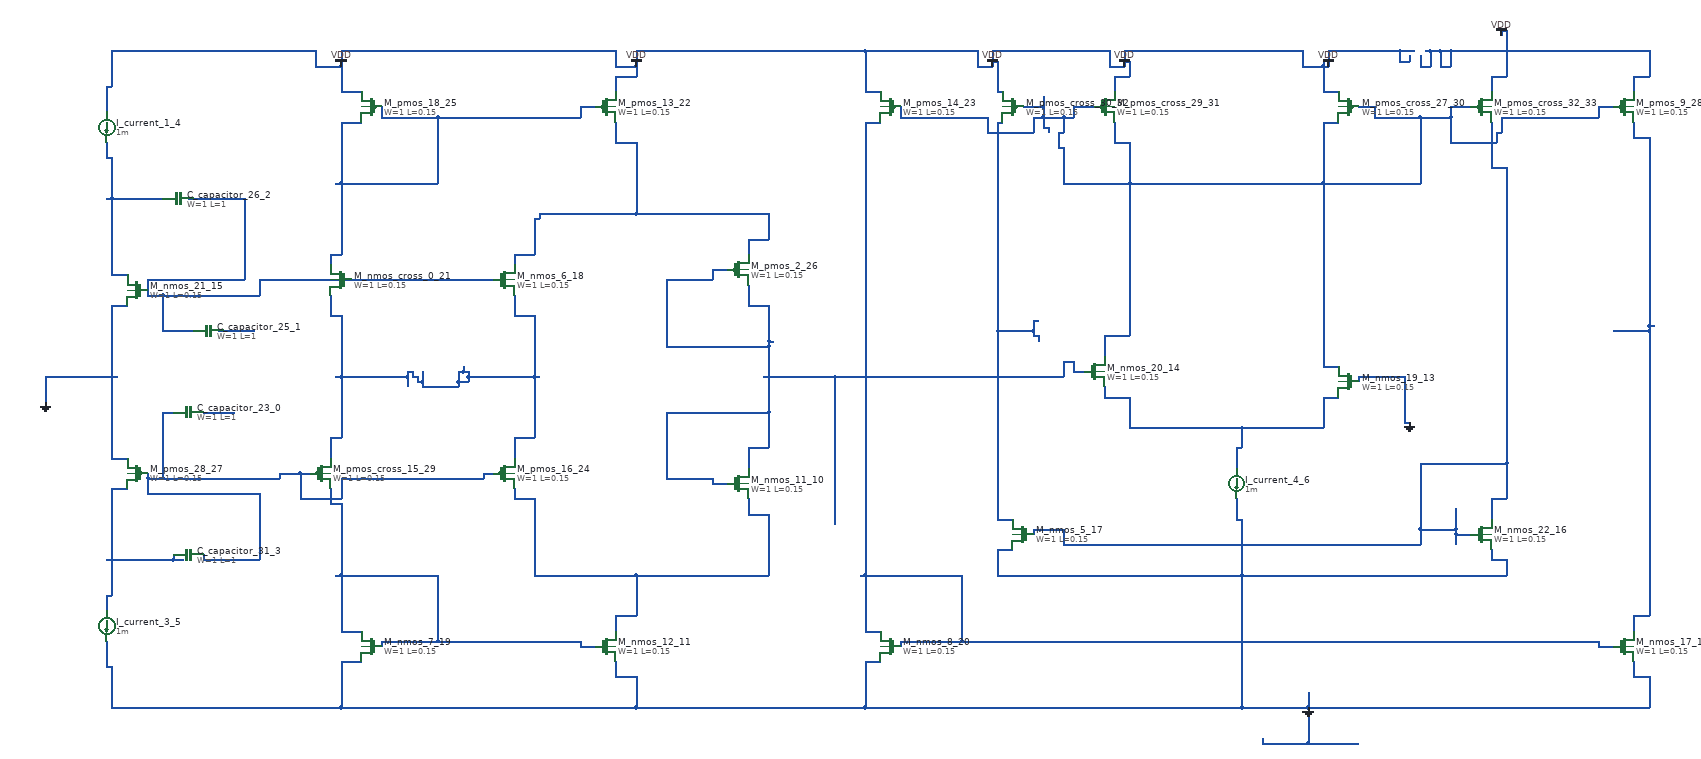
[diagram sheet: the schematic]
v {xschem version=3.4.8 file_version=1.2}
G {}
K {}
V {}
S {}
E {}
C {sky130_fd_pr/cap_mim_m3_1.sym} 340 840 1 0 {name="C_capacitor_23_0" model=cap_mim_m3_1 W=1 L=1 MF=1 spiceprefix=X}
C {sky130_fd_pr/cap_mim_m3_1.sym} 380 680 1 0 {name="C_capacitor_25_1" model=cap_mim_m3_1 W=1 L=1 MF=1 spiceprefix=X}
C {sky130_fd_pr/cap_mim_m3_1.sym} 320 420 3 0 {name="C_capacitor_26_2" model=cap_mim_m3_1 W=1 L=1 MF=1 spiceprefix=X}
C {sky130_fd_pr/cap_mim_m3_1.sym} 340 1120 1 0 {name="C_capacitor_31_3" model=cap_mim_m3_1 W=1 L=1 MF=1 spiceprefix=X}
C {devices/isource.sym} 180 280 0 0 {name="I_current_1_4" value=1m}
C {devices/isource.sym} 180 1260 0 0 {name="I_current_3_5" value=1m}
C {devices/isource.sym} 2400 980 0 0 {name="I_current_4_6" value=1m}
C {devices/gnd.sym} 2740 860 0 0 {name="l_gnd_10_7" lab="GND"}
C {devices/gnd.sym} 60 820 0 0 {name="l_gnd_24_8" lab="GND"}
C {devices/gnd.sym} 2540 1420 0 0 {name="l_gnd_40_9" lab="GND"}
C {sky130_fd_pr/nfet3_01v8.sym} 1420 980 0 0 {name="M_nmos_11_10"
W=1
L=0.15
body=GND
nf=1
mult=1
ad="expr('int((@nf + 1)/2) * @W / @nf * 0.29')"
pd="expr('2*int((@nf + 1)/2) * (@W / @nf + 0.29)')"
as="expr('int((@nf + 2)/2) * @W / @nf * 0.29')"
ps="expr('2*int((@nf + 2)/2) * (@W / @nf + 0.29)')"
nrd="expr('0.29 / @W ')" nrs="expr('0.29 / @W ')"
sa=0 sb=0 sd=0
model=nfet_01v8
spiceprefix=X
}
C {sky130_fd_pr/nfet3_01v8.sym} 1160 1300 0 0 {name="M_nmos_12_11"
W=1
L=0.15
body=GND
nf=1
mult=1
ad="expr('int((@nf + 1)/2) * @W / @nf * 0.29')"
pd="expr('2*int((@nf + 1)/2) * (@W / @nf + 0.29)')"
as="expr('int((@nf + 2)/2) * @W / @nf * 0.29')"
ps="expr('2*int((@nf + 2)/2) * (@W / @nf + 0.29)')"
nrd="expr('0.29 / @W ')" nrs="expr('0.29 / @W ')"
sa=0 sb=0 sd=0
model=nfet_01v8
spiceprefix=X
}
C {sky130_fd_pr/nfet3_01v8.sym} 3160 1300 0 0 {name="M_nmos_17_12"
W=1
L=0.15
body=GND
nf=1
mult=1
ad="expr('int((@nf + 1)/2) * @W / @nf * 0.29')"
pd="expr('2*int((@nf + 1)/2) * (@W / @nf + 0.29)')"
as="expr('int((@nf + 2)/2) * @W / @nf * 0.29')"
ps="expr('2*int((@nf + 2)/2) * (@W / @nf + 0.29)')"
nrd="expr('0.29 / @W ')" nrs="expr('0.29 / @W ')"
sa=0 sb=0 sd=0
model=nfet_01v8
spiceprefix=X
}
C {sky130_fd_pr/nfet3_01v8.sym} 2620 780 0 1 {name="M_nmos_19_13"
W=1
L=0.15
body=GND
nf=1
mult=1
ad="expr('int((@nf + 1)/2) * @W / @nf * 0.29')"
pd="expr('2*int((@nf + 1)/2) * (@W / @nf + 0.29)')"
as="expr('int((@nf + 2)/2) * @W / @nf * 0.29')"
ps="expr('2*int((@nf + 2)/2) * (@W / @nf + 0.29)')"
nrd="expr('0.29 / @W ')" nrs="expr('0.29 / @W ')"
sa=0 sb=0 sd=0
model=nfet_01v8
spiceprefix=X
}
C {sky130_fd_pr/nfet3_01v8.sym} 2120 760 0 0 {name="M_nmos_20_14"
W=1
L=0.15
body=GND
nf=1
mult=1
ad="expr('int((@nf + 1)/2) * @W / @nf * 0.29')"
pd="expr('2*int((@nf + 1)/2) * (@W / @nf + 0.29)')"
as="expr('int((@nf + 2)/2) * @W / @nf * 0.29')"
ps="expr('2*int((@nf + 2)/2) * (@W / @nf + 0.29)')"
nrd="expr('0.29 / @W ')" nrs="expr('0.29 / @W ')"
sa=0 sb=0 sd=0
model=nfet_01v8
spiceprefix=X
}
C {sky130_fd_pr/nfet3_01v8.sym} 240 600 0 1 {name="M_nmos_21_15"
W=1
L=0.15
body=GND
nf=1
mult=1
ad="expr('int((@nf + 1)/2) * @W / @nf * 0.29')"
pd="expr('2*int((@nf + 1)/2) * (@W / @nf + 0.29)')"
as="expr('int((@nf + 2)/2) * @W / @nf * 0.29')"
ps="expr('2*int((@nf + 2)/2) * (@W / @nf + 0.29)')"
nrd="expr('0.29 / @W ')" nrs="expr('0.29 / @W ')"
sa=0 sb=0 sd=0
model=nfet_01v8
spiceprefix=X
}
C {sky130_fd_pr/nfet3_01v8.sym} 2880 1080 0 0 {name="M_nmos_22_16"
W=1
L=0.15
body=GND
nf=1
mult=1
ad="expr('int((@nf + 1)/2) * @W / @nf * 0.29')"
pd="expr('2*int((@nf + 1)/2) * (@W / @nf + 0.29)')"
as="expr('int((@nf + 2)/2) * @W / @nf * 0.29')"
ps="expr('2*int((@nf + 2)/2) * (@W / @nf + 0.29)')"
nrd="expr('0.29 / @W ')" nrs="expr('0.29 / @W ')"
sa=0 sb=0 sd=0
model=nfet_01v8
spiceprefix=X
}
C {sky130_fd_pr/nfet3_01v8.sym} 1980 1080 0 1 {name="M_nmos_5_17"
W=1
L=0.15
body=GND
nf=1
mult=1
ad="expr('int((@nf + 1)/2) * @W / @nf * 0.29')"
pd="expr('2*int((@nf + 1)/2) * (@W / @nf + 0.29)')"
as="expr('int((@nf + 2)/2) * @W / @nf * 0.29')"
ps="expr('2*int((@nf + 2)/2) * (@W / @nf + 0.29)')"
nrd="expr('0.29 / @W ')" nrs="expr('0.29 / @W ')"
sa=0 sb=0 sd=0
model=nfet_01v8
spiceprefix=X
}
C {sky130_fd_pr/nfet3_01v8.sym} 960 580 0 0 {name="M_nmos_6_18"
W=1
L=0.15
body=GND
nf=1
mult=1
ad="expr('int((@nf + 1)/2) * @W / @nf * 0.29')"
pd="expr('2*int((@nf + 1)/2) * (@W / @nf + 0.29)')"
as="expr('int((@nf + 2)/2) * @W / @nf * 0.29')"
ps="expr('2*int((@nf + 2)/2) * (@W / @nf + 0.29)')"
nrd="expr('0.29 / @W ')" nrs="expr('0.29 / @W ')"
sa=0 sb=0 sd=0
model=nfet_01v8
spiceprefix=X
}
C {sky130_fd_pr/nfet3_01v8.sym} 700 1300 0 1 {name="M_nmos_7_19"
W=1
L=0.15
body=GND
nf=1
mult=1
ad="expr('int((@nf + 1)/2) * @W / @nf * 0.29')"
pd="expr('2*int((@nf + 1)/2) * (@W / @nf + 0.29)')"
as="expr('int((@nf + 2)/2) * @W / @nf * 0.29')"
ps="expr('2*int((@nf + 2)/2) * (@W / @nf + 0.29)')"
nrd="expr('0.29 / @W ')" nrs="expr('0.29 / @W ')"
sa=0 sb=0 sd=0
model=nfet_01v8
spiceprefix=X
}
C {sky130_fd_pr/nfet3_01v8.sym} 1720 1300 0 1 {name="M_nmos_8_20"
W=1
L=0.15
body=GND
nf=1
mult=1
ad="expr('int((@nf + 1)/2) * @W / @nf * 0.29')"
pd="expr('2*int((@nf + 1)/2) * (@W / @nf + 0.29)')"
as="expr('int((@nf + 2)/2) * @W / @nf * 0.29')"
ps="expr('2*int((@nf + 2)/2) * (@W / @nf + 0.29)')"
nrd="expr('0.29 / @W ')" nrs="expr('0.29 / @W ')"
sa=0 sb=0 sd=0
model=nfet_01v8
spiceprefix=X
}
C {sky130_fd_pr/nfet3_01v8.sym} 640 580 0 1 {name="M_nmos_cross_0_21"
W=1
L=0.15
body=GND
nf=1
mult=1
ad="expr('int((@nf + 1)/2) * @W / @nf * 0.29')"
pd="expr('2*int((@nf + 1)/2) * (@W / @nf + 0.29)')"
as="expr('int((@nf + 2)/2) * @W / @nf * 0.29')"
ps="expr('2*int((@nf + 2)/2) * (@W / @nf + 0.29)')"
nrd="expr('0.29 / @W ')" nrs="expr('0.29 / @W ')"
sa=0 sb=0 sd=0
model=nfet_01v8
spiceprefix=X
}
C {sky130_fd_pr/pfet3_01v8.sym} 1160 240 0 0 {name="M_pmos_13_22"
W=1
L=0.15
body=VDD
nf=1
mult=1
ad="expr('int((@nf + 1)/2) * @W / @nf * 0.29')"
pd="expr('2*int((@nf + 1)/2) * (@W / @nf + 0.29)')"
as="expr('int((@nf + 2)/2) * @W / @nf * 0.29')"
ps="expr('2*int((@nf + 2)/2) * (@W / @nf + 0.29)')"
nrd="expr('0.29 / @W ')" nrs="expr('0.29 / @W ')"
sa=0 sb=0 sd=0
model=pfet_01v8
spiceprefix=X
}
C {sky130_fd_pr/pfet3_01v8.sym} 1720 240 0 1 {name="M_pmos_14_23"
W=1
L=0.15
body=VDD
nf=1
mult=1
ad="expr('int((@nf + 1)/2) * @W / @nf * 0.29')"
pd="expr('2*int((@nf + 1)/2) * (@W / @nf + 0.29)')"
as="expr('int((@nf + 2)/2) * @W / @nf * 0.29')"
ps="expr('2*int((@nf + 2)/2) * (@W / @nf + 0.29)')"
nrd="expr('0.29 / @W ')" nrs="expr('0.29 / @W ')"
sa=0 sb=0 sd=0
model=pfet_01v8
spiceprefix=X
}
C {sky130_fd_pr/pfet3_01v8.sym} 960 960 0 0 {name="M_pmos_16_24"
W=1
L=0.15
body=VDD
nf=1
mult=1
ad="expr('int((@nf + 1)/2) * @W / @nf * 0.29')"
pd="expr('2*int((@nf + 1)/2) * (@W / @nf + 0.29)')"
as="expr('int((@nf + 2)/2) * @W / @nf * 0.29')"
ps="expr('2*int((@nf + 2)/2) * (@W / @nf + 0.29)')"
nrd="expr('0.29 / @W ')" nrs="expr('0.29 / @W ')"
sa=0 sb=0 sd=0
model=pfet_01v8
spiceprefix=X
}
C {sky130_fd_pr/pfet3_01v8.sym} 700 240 0 1 {name="M_pmos_18_25"
W=1
L=0.15
body=VDD
nf=1
mult=1
ad="expr('int((@nf + 1)/2) * @W / @nf * 0.29')"
pd="expr('2*int((@nf + 1)/2) * (@W / @nf + 0.29)')"
as="expr('int((@nf + 2)/2) * @W / @nf * 0.29')"
ps="expr('2*int((@nf + 2)/2) * (@W / @nf + 0.29)')"
nrd="expr('0.29 / @W ')" nrs="expr('0.29 / @W ')"
sa=0 sb=0 sd=0
model=pfet_01v8
spiceprefix=X
}
C {sky130_fd_pr/pfet3_01v8.sym} 1420 560 0 0 {name="M_pmos_2_26"
W=1
L=0.15
body=VDD
nf=1
mult=1
ad="expr('int((@nf + 1)/2) * @W / @nf * 0.29')"
pd="expr('2*int((@nf + 1)/2) * (@W / @nf + 0.29)')"
as="expr('int((@nf + 2)/2) * @W / @nf * 0.29')"
ps="expr('2*int((@nf + 2)/2) * (@W / @nf + 0.29)')"
nrd="expr('0.29 / @W ')" nrs="expr('0.29 / @W ')"
sa=0 sb=0 sd=0
model=pfet_01v8
spiceprefix=X
}
C {sky130_fd_pr/pfet3_01v8.sym} 240 960 0 1 {name="M_pmos_28_27"
W=1
L=0.15
body=VDD
nf=1
mult=1
ad="expr('int((@nf + 1)/2) * @W / @nf * 0.29')"
pd="expr('2*int((@nf + 1)/2) * (@W / @nf + 0.29)')"
as="expr('int((@nf + 2)/2) * @W / @nf * 0.29')"
ps="expr('2*int((@nf + 2)/2) * (@W / @nf + 0.29)')"
nrd="expr('0.29 / @W ')" nrs="expr('0.29 / @W ')"
sa=0 sb=0 sd=0
model=pfet_01v8
spiceprefix=X
}
C {sky130_fd_pr/pfet3_01v8.sym} 3160 240 0 0 {name="M_pmos_9_28"
W=1
L=0.15
body=VDD
nf=1
mult=1
ad="expr('int((@nf + 1)/2) * @W / @nf * 0.29')"
pd="expr('2*int((@nf + 1)/2) * (@W / @nf + 0.29)')"
as="expr('int((@nf + 2)/2) * @W / @nf * 0.29')"
ps="expr('2*int((@nf + 2)/2) * (@W / @nf + 0.29)')"
nrd="expr('0.29 / @W ')" nrs="expr('0.29 / @W ')"
sa=0 sb=0 sd=0
model=pfet_01v8
spiceprefix=X
}
C {sky130_fd_pr/pfet3_01v8.sym} 600 960 0 0 {name="M_pmos_cross_15_29"
W=1
L=0.15
body=VDD
nf=1
mult=1
ad="expr('int((@nf + 1)/2) * @W / @nf * 0.29')"
pd="expr('2*int((@nf + 1)/2) * (@W / @nf + 0.29)')"
as="expr('int((@nf + 2)/2) * @W / @nf * 0.29')"
ps="expr('2*int((@nf + 2)/2) * (@W / @nf + 0.29)')"
nrd="expr('0.29 / @W ')" nrs="expr('0.29 / @W ')"
sa=0 sb=0 sd=0
model=pfet_01v8
spiceprefix=X
}
C {sky130_fd_pr/pfet3_01v8.sym} 2620 240 0 1 {name="M_pmos_cross_27_30"
W=1
L=0.15
body=VDD
nf=1
mult=1
ad="expr('int((@nf + 1)/2) * @W / @nf * 0.29')"
pd="expr('2*int((@nf + 1)/2) * (@W / @nf + 0.29)')"
as="expr('int((@nf + 2)/2) * @W / @nf * 0.29')"
ps="expr('2*int((@nf + 2)/2) * (@W / @nf + 0.29)')"
nrd="expr('0.29 / @W ')" nrs="expr('0.29 / @W ')"
sa=0 sb=0 sd=0
model=pfet_01v8
spiceprefix=X
}
C {sky130_fd_pr/pfet3_01v8.sym} 2140 240 0 0 {name="M_pmos_cross_29_31"
W=1
L=0.15
body=VDD
nf=1
mult=1
ad="expr('int((@nf + 1)/2) * @W / @nf * 0.29')"
pd="expr('2*int((@nf + 1)/2) * (@W / @nf + 0.29)')"
as="expr('int((@nf + 2)/2) * @W / @nf * 0.29')"
ps="expr('2*int((@nf + 2)/2) * (@W / @nf + 0.29)')"
nrd="expr('0.29 / @W ')" nrs="expr('0.29 / @W ')"
sa=0 sb=0 sd=0
model=pfet_01v8
spiceprefix=X
}
C {sky130_fd_pr/pfet3_01v8.sym} 1960 240 0 1 {name="M_pmos_cross_30_32"
W=1
L=0.15
body=VDD
nf=1
mult=1
ad="expr('int((@nf + 1)/2) * @W / @nf * 0.29')"
pd="expr('2*int((@nf + 1)/2) * (@W / @nf + 0.29)')"
as="expr('int((@nf + 2)/2) * @W / @nf * 0.29')"
ps="expr('2*int((@nf + 2)/2) * (@W / @nf + 0.29)')"
nrd="expr('0.29 / @W ')" nrs="expr('0.29 / @W ')"
sa=0 sb=0 sd=0
model=pfet_01v8
spiceprefix=X
}
C {sky130_fd_pr/pfet3_01v8.sym} 2880 240 0 0 {name="M_pmos_cross_32_33"
W=1
L=0.15
body=VDD
nf=1
mult=1
ad="expr('int((@nf + 1)/2) * @W / @nf * 0.29')"
pd="expr('2*int((@nf + 1)/2) * (@W / @nf + 0.29)')"
as="expr('int((@nf + 2)/2) * @W / @nf * 0.29')"
ps="expr('2*int((@nf + 2)/2) * (@W / @nf + 0.29)')"
nrd="expr('0.29 / @W ')" nrs="expr('0.29 / @W ')"
sa=0 sb=0 sd=0
model=pfet_01v8
spiceprefix=X
}
C {devices/vdd.sym} 2920 100 0 0 {name="l_vdd_33_34" lab="VDD"}
C {devices/vdd.sym} 640 160 0 0 {name="l_vdd_34_35" lab="VDD"}
C {devices/vdd.sym} 1220 160 0 0 {name="l_vdd_35_36" lab="VDD"}
C {devices/vdd.sym} 1920 160 0 0 {name="l_vdd_36_37" lab="VDD"}
C {devices/vdd.sym} 2580 160 0 0 {name="l_vdd_37_38" lab="VDD"}
C {devices/vdd.sym} 2180 160 0 0 {name="l_vdd_38_39" lab="VDD"}
N 370 1130 480 1130 {}
N 560 1010 640 1010 {}
N 260 1000 480 1000 {}
N 260 970 290 970 {}
N 290 970 520 970 {}
N 640 970 920 970 {}
N 520 960 560 960 {}
N 560 960 580 960 {}
N 920 960 940 960 {}
N 290 840 310 840 {}
N 310 840 330 840 {}
N 260 1000 260 970 {}
N 260 970 260 960 {}
N 290 970 290 840 {}
N 370 1130 370 1120 {}
N 480 1130 480 1000 {}
N 520 970 520 960 {}
N 560 1010 560 960 {}
N 640 1010 640 970 {}
N 920 970 920 960 {}
N 370 840 430 840 {}
N 3110 1300 3140 1300 {}
N 1740 1290 1860 1290 {}
N 1860 1290 3110 1290 {}
N 1670 1270 1700 1270 {}
N 1660 1160 1670 1160 {}
N 1670 1160 1860 1160 {}
N 1670 270 1700 270 {}
N 1670 1270 1670 1160 {}
N 1670 1160 1670 270 {}
N 1740 1300 1740 1290 {}
N 1860 1290 1860 1160 {}
N 3110 1300 3110 1290 {}
N 2570 750 2600 750 {}
N 2140 690 2190 690 {}
N 2060 390 2190 390 {}
N 2190 390 2570 390 {}
N 2570 390 2760 390 {}
N 2050 320 2060 320 {}
N 2160 310 2190 310 {}
N 2820 310 2910 310 {}
N 1910 290 2000 290 {}
N 2050 290 2060 290 {}
N 2910 290 2920 290 {}
N 2020 280 2030 280 {}
N 2570 270 2600 270 {}
N 1740 260 1910 260 {}
N 2000 260 2020 260 {}
N 2020 260 2060 260 {}
N 2060 260 2080 260 {}
N 2670 260 2760 260 {}
N 2760 260 2820 260 {}
N 2920 260 3110 260 {}
N 1980 240 2020 240 {}
N 2080 240 2120 240 {}
N 2640 240 2670 240 {}
N 2820 240 2860 240 {}
N 3110 240 3140 240 {}
N 1740 260 1740 240 {}
N 1910 290 1910 260 {}
N 2000 290 2000 260 {}
N 2020 280 2020 260 {}
N 2020 260 2020 240 {}
N 2020 240 2020 220 {}
N 2030 290 2030 280 {}
N 2050 320 2050 290 {}
N 2060 390 2060 320 {}
N 2060 290 2060 260 {}
N 2080 260 2080 240 {}
N 2140 730 2140 690 {}
N 2160 310 2160 270 {}
N 2190 690 2190 390 {}
N 2190 390 2190 310 {}
N 2570 750 2570 390 {}
N 2570 390 2570 270 {}
N 2670 260 2670 240 {}
N 2760 390 2760 260 {}
N 2820 310 2820 260 {}
N 2820 260 2820 240 {}
N 2910 310 2910 290 {}
N 2920 290 2920 260 {}
N 3110 260 3110 240 {}
N 400 680 410 680 {}
N 410 680 470 680 {}
N 190 570 220 570 {}
N 180 420 190 420 {}
N 190 420 290 420 {}
N 290 420 300 420 {}
N 180 340 190 340 {}
N 180 340 180 310 {}
N 190 570 190 420 {}
N 190 420 190 340 {}
N 1930 1050 1960 1050 {}
N 2000 690 2010 690 {}
N 1930 680 2000 680 {}
N 2000 660 2010 660 {}
N 1930 270 1940 270 {}
N 1930 1050 1930 680 {}
N 1930 680 1930 270 {}
N 2000 690 2000 680 {}
N 2000 680 2000 660 {}
N 2010 700 2010 690 {}
N 980 530 1020 530 {}
N 1440 500 1480 500 {}
N 1020 460 1030 460 {}
N 1030 450 1220 450 {}
N 1220 450 1480 450 {}
N 1180 310 1220 310 {}
N 980 550 980 530 {}
N 1020 530 1020 460 {}
N 1030 460 1030 450 {}
N 1180 310 1180 270 {}
N 1220 450 1220 310 {}
N 1440 530 1440 500 {}
N 1480 500 1480 450 {}
N 620 530 640 530 {}
N 630 390 640 390 {}
N 640 390 830 390 {}
N 640 270 680 270 {}
N 720 260 830 260 {}
N 830 260 1110 260 {}
N 1110 240 1140 240 {}
N 620 550 620 530 {}
N 640 530 640 390 {}
N 640 390 640 270 {}
N 720 260 720 240 {}
N 830 390 830 260 {}
N 1110 260 1110 240 {}
N 620 890 640 890 {}
N 980 890 1020 890 {}
N 800 790 870 790 {}
N 790 780 800 780 {}
N 870 780 890 780 {}
N 630 770 640 770 {}
N 640 770 770 770 {}
N 780 770 790 770 {}
N 890 770 1020 770 {}
N 1020 770 1030 770 {}
N 770 760 780 760 {}
N 870 760 880 760 {}
N 880 760 890 760 {}
N 620 650 640 650 {}
N 980 650 1020 650 {}
N 620 930 620 890 {}
N 620 650 620 610 {}
N 640 890 640 770 {}
N 640 770 640 650 {}
N 770 790 770 770 {}
N 770 770 770 760 {}
N 780 770 780 760 {}
N 790 780 790 770 {}
N 800 790 800 780 {}
N 800 780 800 760 {}
N 870 790 870 780 {}
N 870 780 870 760 {}
N 880 760 880 750 {}
N 890 780 890 770 {}
N 890 770 890 760 {}
N 980 930 980 890 {}
N 980 650 980 610 {}
N 1020 890 1020 770 {}
N 1020 770 1020 650 {}
N 640 210 680 210 {}
N 1670 210 1700 210 {}
N 1930 210 1940 210 {}
N 2570 210 2600 210 {}
N 180 200 190 200 {}
N 1180 180 1220 180 {}
N 2160 180 2190 180 {}
N 2900 180 2930 180 {}
N 3180 180 3210 180 {}
N 590 160 640 160 {}
N 1180 160 1220 160 {}
N 1890 160 1920 160 {}
N 2150 160 2180 160 {}
N 2530 160 2570 160 {}
N 2570 160 2580 160 {}
N 2760 160 2780 160 {}
N 2800 160 2820 160 {}
N 1920 150 1930 150 {}
N 2180 150 2190 150 {}
N 2720 150 2740 150 {}
N 190 130 590 130 {}
N 640 130 1180 130 {}
N 1220 130 1670 130 {}
N 1670 130 1890 130 {}
N 1920 130 2150 130 {}
N 2180 130 2530 130 {}
N 2580 130 2720 130 {}
N 2720 130 2750 130 {}
N 2770 130 2780 130 {}
N 2780 130 2800 130 {}
N 2800 130 2820 130 {}
N 2820 130 2930 130 {}
N 2930 130 3210 130 {}
N 2920 90 2930 90 {}
N 180 250 180 200 {}
N 190 200 190 130 {}
N 590 160 590 130 {}
N 640 210 640 160 {}
N 640 160 640 130 {}
N 1180 210 1180 180 {}
N 1180 160 1180 130 {}
N 1220 180 1220 160 {}
N 1220 160 1220 130 {}
N 1670 210 1670 130 {}
N 1890 160 1890 130 {}
N 1920 160 1920 150 {}
N 1920 150 1920 130 {}
N 1930 210 1930 150 {}
N 2150 160 2150 130 {}
N 2160 210 2160 180 {}
N 2180 160 2180 150 {}
N 2180 150 2180 130 {}
N 2190 180 2190 150 {}
N 2530 160 2530 130 {}
N 2570 210 2570 160 {}
N 2570 160 2570 150 {}
N 2580 160 2580 130 {}
N 2720 150 2720 130 {}
N 2740 150 2740 140 {}
N 2760 160 2760 140 {}
N 2780 160 2780 130 {}
N 2800 160 2800 130 {}
N 2820 160 2820 130 {}
N 2900 210 2900 180 {}
N 2920 100 2920 90 {}
N 2930 180 2930 130 {}
N 2930 130 2930 90 {}
N 3180 210 3180 180 {}
N 3210 180 3210 130 {}
N 2060 1100 2760 1100 {}
N 2830 1080 2860 1080 {}
N 2000 1070 2060 1070 {}
N 2760 1070 2830 1070 {}
N 2900 1010 2930 1010 {}
N 2760 940 2930 940 {}
N 2900 360 2930 360 {}
N 2000 1080 2000 1070 {}
N 2060 1100 2060 1070 {}
N 2760 1100 2760 1070 {}
N 2760 1070 2760 940 {}
N 2830 1100 2830 1080 {}
N 2830 1080 2830 1070 {}
N 2830 1070 2830 1030 {}
N 2900 1050 2900 1010 {}
N 2900 360 2900 270 {}
N 2930 1010 2930 940 {}
N 2930 940 2930 360 {}
N 180 1200 190 1200 {}
N 180 1130 190 1130 {}
N 190 1130 310 1130 {}
N 310 1130 330 1130 {}
N 190 990 220 990 {}
N 180 1230 180 1200 {}
N 190 1200 190 1130 {}
N 190 1130 190 990 {}
N 310 1130 310 1120 {}
N 2400 910 2410 910 {}
N 2190 870 2410 870 {}
N 2410 870 2570 870 {}
N 2140 810 2190 810 {}
N 2570 810 2600 810 {}
N 2140 810 2140 790 {}
N 2190 870 2190 810 {}
N 2400 950 2400 910 {}
N 2410 910 2410 870 {}
N 2570 870 2570 810 {}
N 2450 1490 2540 1490 {}
N 2540 1490 2640 1490 {}
N 190 1420 640 1420 {}
N 640 1420 1220 1420 {}
N 1220 1420 1670 1420 {}
N 1670 1420 2410 1420 {}
N 2410 1420 2540 1420 {}
N 2540 1420 3210 1420 {}
N 1180 1360 1220 1360 {}
N 3180 1360 3210 1360 {}
N 180 1340 190 1340 {}
N 640 1330 680 1330 {}
N 1670 1330 1700 1330 {}
N 1930 1160 2410 1160 {}
N 2410 1160 2930 1160 {}
N 2900 1130 2930 1130 {}
N 1930 1110 1960 1110 {}
N 2400 1050 2410 1050 {}
N 190 930 220 930 {}
N 2730 860 2740 860 {}
N 60 770 190 770 {}
N 190 770 200 770 {}
N 2640 770 2730 770 {}
N 190 630 220 630 {}
N 60 820 60 770 {}
N 180 1340 180 1290 {}
N 190 1420 190 1340 {}
N 190 930 190 770 {}
N 190 770 190 630 {}
N 640 1420 640 1330 {}
N 1180 1360 1180 1330 {}
N 1220 1420 1220 1360 {}
N 1670 1420 1670 1330 {}
N 1930 1160 1930 1110 {}
N 2400 1050 2400 1010 {}
N 2410 1420 2410 1160 {}
N 2410 1160 2410 1050 {}
N 2450 1490 2450 1480 {}
N 2540 1490 2540 1420 {}
N 2540 1420 2540 1390 {}
N 2640 780 2640 770 {}
N 2730 860 2730 770 {}
N 2900 1130 2900 1110 {}
N 2930 1160 2930 1130 {}
N 3180 1360 3180 1330 {}
N 3210 1420 3210 1360 {}
N 1370 980 1400 980 {}
N 1280 970 1370 970 {}
N 1440 910 1480 910 {}
N 1280 840 1480 840 {}
N 1470 770 1480 770 {}
N 1480 770 1610 770 {}
N 1610 770 2060 770 {}
N 2080 760 2100 760 {}
N 2060 740 2080 740 {}
N 1280 710 1480 710 {}
N 1480 700 1490 700 {}
N 1440 630 1480 630 {}
N 1280 580 1370 580 {}
N 1370 560 1400 560 {}
N 1280 970 1280 840 {}
N 1280 710 1280 580 {}
N 1370 980 1370 970 {}
N 1370 580 1370 560 {}
N 1440 950 1440 910 {}
N 1440 630 1440 590 {}
N 1480 910 1480 840 {}
N 1480 840 1480 770 {}
N 1480 770 1480 710 {}
N 1480 710 1480 700 {}
N 1480 700 1480 630 {}
N 1610 1060 1610 770 {}
N 2060 770 2060 740 {}
N 2080 760 2080 740 {}
N 1180 1240 1220 1240 {}
N 1020 1160 1220 1160 {}
N 1220 1160 1480 1160 {}
N 1440 1040 1480 1040 {}
N 980 1010 1020 1010 {}
N 980 1010 980 990 {}
N 1020 1160 1020 1010 {}
N 1180 1270 1180 1240 {}
N 1220 1240 1220 1160 {}
N 1440 1040 1440 1010 {}
N 1480 1160 1480 1040 {}
N 290 680 350 680 {}
N 350 680 360 680 {}
N 260 610 290 610 {}
N 290 610 480 610 {}
N 260 580 450 580 {}
N 480 580 660 580 {}
N 660 580 940 580 {}
N 340 420 350 420 {}
N 350 420 450 420 {}
N 260 610 260 600 {}
N 260 600 260 580 {}
N 290 680 290 610 {}
N 450 580 450 420 {}
N 480 610 480 580 {}
N 1110 1300 1140 1300 {}
N 720 1290 830 1290 {}
N 830 1290 1110 1290 {}
N 640 1270 680 1270 {}
N 630 1160 640 1160 {}
N 640 1160 830 1160 {}
N 620 1020 640 1020 {}
N 620 1020 620 990 {}
N 640 1270 640 1160 {}
N 640 1160 640 1020 {}
N 720 1300 720 1290 {}
N 830 1290 830 1160 {}
N 1110 1300 1110 1290 {}
N 3180 1240 3210 1240 {}
N 3140 680 3210 680 {}
N 3210 670 3220 670 {}
N 3180 300 3210 300 {}
N 3180 1270 3180 1240 {}
N 3180 300 3180 270 {}
N 3210 1240 3210 680 {}
N 3210 680 3210 670 {}
N 3210 670 3210 300 {}
